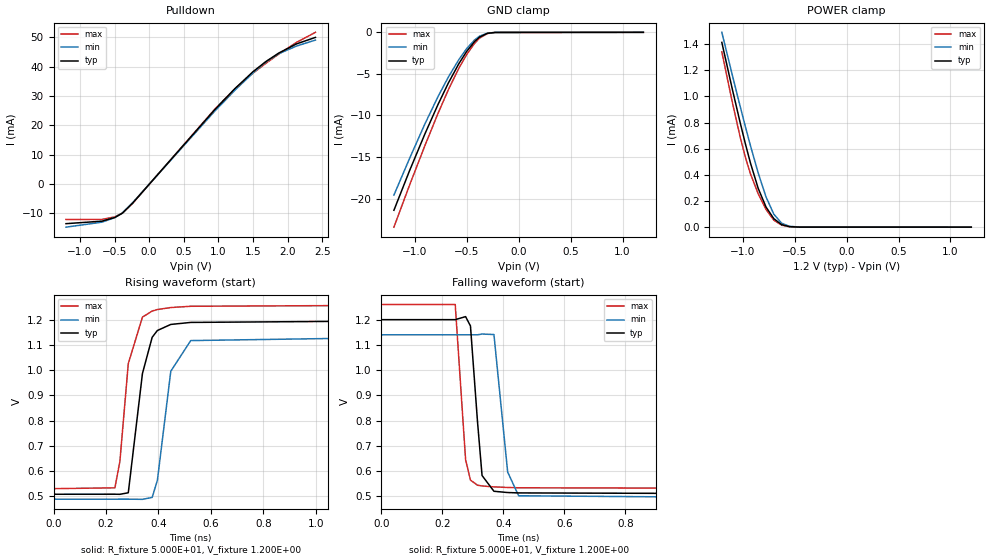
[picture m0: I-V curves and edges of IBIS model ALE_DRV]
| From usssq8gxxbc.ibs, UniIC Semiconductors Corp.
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|   Model ALE_DRV
[Model] ALE_DRV
Model_type Open_sink
Polarity   Non-Inverting
Enable   Active-High
Vmeas =  6.000E-01
Rref =  5.000E+01
Vref =  1.200E+00
C_comp   4.640E-13   4.486E-13   4.837E-13
C_comp_pulldown   3.035E-13   2.970E-13   3.357E-13
C_comp_power_clamp   1.302E-13   1.265E-13   1.391E-13
[Model Spec]
Vmeas   6.000E-01   5.700E-01   6.300E-01
Vref   1.200E+00   1.140E+00   1.260E+00
Rref   5.000E+01   5.000E+01   5.000E+01
[Temperature Range]   4.500E+01   9.500E+01   0.000E+00
[Voltage Range]   1.200E+00   1.140E+00   1.260E+00
[C Comp Corner]
C_comp_pulldown   3.035E-13   2.970E-13   3.357E-13
C_comp_power_clamp   1.391E-13   1.302E-13   1.265E-13
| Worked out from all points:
|   slope of the pulldown table from 0 to 0.18 V, typ, clamps not added: 36.4 ohm
|   GND clamp passes 1 mA (typ) near -0.41 V on its own axis
|   POWER clamp passes 1 mA (typ) near -1.08 V on its own axis
|   rising waveform, R_fixture 5.000E+01, V_fixture 1.200E+00: 20-80 % time 45.7ps typ, 48.5ps min, 43.4ps max; typ from 0.508 V to 1.2 V
|   falling waveform, R_fixture 5.000E+01, V_fixture 1.200E+00: 20-80 % time 22.2ps typ, 26.4ps min, 20.2ps max; typ from 1.2 V to 0.508 V
[Pulldown]
|Voltage   I(typ)   I(min)   I(max)
-1.2V     -13.58mA   -14.77mA   -12.15mA
-682mV    -12.73mA   -13.07mA   -12.13mA
-497mV    -11.49mA   -11.54mA   -11.27mA
-386mV    -9.998mA   -9.897mA   -9.976mA
-238mV    -6.556mA   -6.414mA   -6.639mA
946mV     25.31mA    24.82mA    25.48mA
1.242V    32.61mA    32.07mA    32.58mA
1.501V    38.36mA    37.95mA    37.85mA
1.686V    41.79mA    41.61mA    41.18mA
1.871V    44.68mA    44.45mA    44.32mA
2.13V     47.83mA    47.09mA    48.36mA
2.4V      50.02mA    49.11mA    51.75mA
[GND_clamp]
|Voltage   I(typ)   I(min)   I(max)
-1.2V     -21.41mA   -19.58mA   -23.44mA
-1.05V    -16.66mA   -15.19mA   -18.4mA
-900mV    -12.17mA   -10.97mA   -13.57mA
-775mV    -8.663mA   -7.718mA   -9.731mA
-675mV    -6.07mA    -5.357mA   -6.872mA
-575mV    -3.768mA   -3.276mA   -4.32mA
-500mV    -2.298mA   -1.958mA   -2.676mA
-425mV    -1.123mA   -929.9uA   -1.344mA
-375mV    -561.1uA   -457.6uA   -689.4uA
-300mV    -117.3uA   -101.1uA   -143uA
-225mV    -12.89uA   -13.99uA   -12.5uA
1.2V      0A         0A         0A
[POWER_clamp]
|Voltage   I(typ)   I(min)   I(max)
-1.2V     1.414mA    1.491mA    1.341mA
-1.1V     1.059mA    1.166mA    959.1uA
-1.025V   804.3uA    928.4uA    694.9uA
-975mV    642.7uA    774.1uA    539.3uA
-925mV    491.6uA    624.7uA    408.5uA
-850mV    296.4uA    414.1uA    255.5uA
-775mV    154.4uA    231.8uA    135.8uA
-700mV    65.09uA    99.41uA    53.85uA
-625mV    19.16uA    30.35uA    15.25uA
-550mV    3.935uA    6.436uA    3.094uA
-450mV    345.4nA    637.5nA    233.6nA
1.2V      0A         0A         1.66nA
[Ramp]
| variable   typ   min   max
dV/dt_r   4.152E-01/4.872E-11   3.909E-01/5.210E-11   4.379E-01/4.447E-11
dV/dt_f   4.152E-01/2.548E-11   3.909E-01/3.119E-11   4.379E-01/2.228E-11
R_load = 5.000E+01
[Rising Waveform]
R_fixture= 5.000E+01
V_fixture= 1.200E+00
V_fixture_min= 1.140E+00
V_fixture_max= 1.260E+00
|time   V(typ)   V(min)   V(max)
0s        508.1mV    488.4mV    530.2mV
234ps     508.2mV    488.5mV    533.5mV
253ps     507.8mV    488.6mV    638.2mV
285ps     513.9mV    488.6mV    1.026V
339ps     986.7mV    487.9mV    1.21V
376ps     1.13V      495.4mV    1.234V
396ps     1.157V     563.6mV    1.24V
447ps     1.181V     995.5mV    1.248V
523ps     1.189V     1.117V     1.253V
2ns       1.2V       1.14V      1.26V
[Falling Waveform]
R_fixture= 5.000E+01
V_fixture= 1.200E+00
V_fixture_min= 1.140E+00
V_fixture_max= 1.260E+00
|time   V(typ)   V(min)   V(max)
0s        1.2V       1.14V      1.26V
242ps     1.2V       1.14V      1.26V
276ps     1.212V     1.14V      645.2mV
292ps     1.175V     1.14V      564.7mV
315ps     797.2mV    1.14V      544.4mV
330ps     582.8mV    1.143V     541.4mV
369ps     520.3mV    1.141V     537.7mV
414ps     515.3mV    596.4mV    535.4mV
450ps     513.8mV    502.5mV    534.1mV
2ns       508.1mV    488.4mV    530.2mV
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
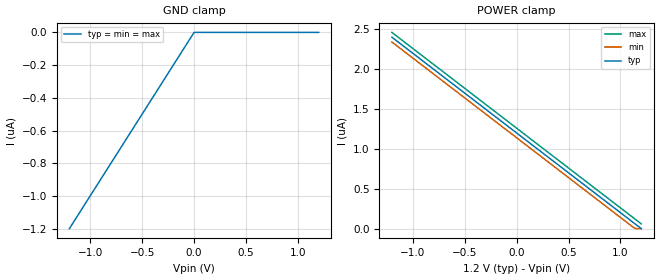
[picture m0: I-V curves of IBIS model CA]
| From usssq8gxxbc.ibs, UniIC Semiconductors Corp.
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|   Model CA
[Model] CA
Model_type Input
Polarity   Non-Inverting
Enable   Active-High
Vinl =  5.100E-01
Vinh =  6.900E-01
C_comp   -0.000E+00   -0.000E+00   -0.000E+00
[Model Spec]
Vinh   6.900E-01   6.600E-01   7.200E-01
Vinl   5.100E-01   4.800E-01   5.400E-01
[Temperature Range]   4.500E+01   9.500E+01   0.000E+00
[Voltage Range]   1.200E+00   1.140E+00   1.260E+00
[C Comp Corner]
C_comp   -0.000E+00   -0.000E+00   -0.000E+00
[GND_clamp]
|Voltage   I(typ)   I(min)   I(max)
-1.2V     -1.2uA     -1.2uA     -1.2uA
-1.075V   -1.075uA   -1.075uA   -1.075uA
0V        0A         0A         0A
1.2V      0A         0A         0A
[POWER_clamp]
|Voltage   I(typ)   I(min)   I(max)
-1.2V     2.4uA      2.34uA     2.46uA
1.125V    75nA       15nA       135nA
1.15V     50nA       0A         110nA
1.2V      0A         0A         60nA
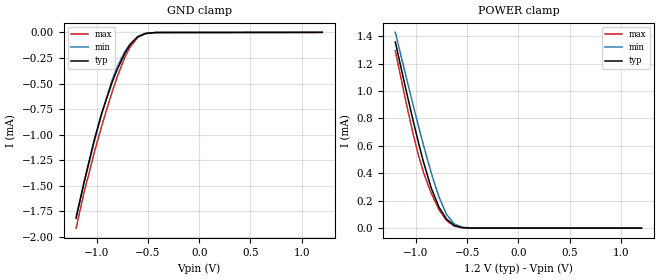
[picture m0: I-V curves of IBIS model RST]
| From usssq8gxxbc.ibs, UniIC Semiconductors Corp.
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|   Model RST
[Model] RST
Model_type Input
Polarity   Non-Inverting
Enable   Active-High
Vinl =  2.400E-01
Vinh =  9.600E-01
C_comp   3.325E-13   3.183E-13   3.499E-13
C_comp_power_clamp   1.183E-13   1.092E-13   1.358E-13
C_comp_gnd_clamp   1.941E-13   1.623E-13   2.205E-13
[Model Spec]
Vinh   9.600E-01   9.120E-01   1.008E+00
Vinl   2.400E-01   2.280E-01   2.520E-01
[Temperature Range]   4.500E+01   9.500E+01   0.000E+00
[Voltage Range]   1.200E+00   1.140E+00   1.260E+00
[C Comp Corner]
C_comp_power_clamp   1.183E-13   1.358E-13   1.092E-13
C_comp_gnd_clamp   1.941E-13   1.623E-13   2.205E-13
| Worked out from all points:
|   GND clamp passes 1 mA (typ) near -1.01 V on its own axis
|   POWER clamp passes 1 mA (typ) near -1.09 V on its own axis
[GND_clamp]
|Voltage   I(typ)   I(min)   I(max)
-1.2V     -1.816mA   -1.797mA   -1.913mA
-1.125V   -1.474mA   -1.481mA   -1.574mA
-1.025V   -1.057mA   -1.076mA   -1.18mA
-950mV    -787.4uA   -793.9uA   -912.4uA
-850mV    -490.5uA   -468.5uA   -584.5uA
-800mV    -364.5uA   -337.8uA   -436uA
-725mV    -204.3uA   -187.1uA   -243.5uA
-675mV    -121.3uA   -114.6uA   -144.9uA
-600mV    -42.01uA   -44.1uA    -50.98uA
-525mV    -10.75uA   -12.45uA   -11.9uA
-425mV    -1.264uA   -1.773uA   -1.033uA
1.2V      0A         0A         0A
[POWER_clamp]
|Voltage   I(typ)   I(min)   I(max)
-1.2V     1.357mA    1.427mA    1.293mA
-1.1V     1.021mA    1.119mA    932.1uA
-1.025V   779.4uA    893uA      681.4uA
-975mV    625.7uA    746.2uA    532.4uA
-925mV    481.4uA    603.8uA    405.5uA
-850mV    293uA      402.8uA    254.4uA
-775mV    153.6uA    227.5uA    135.3uA
-700mV    64.89uA    98.55uA    53.68uA
-625mV    19.08uA    30.18uA    15.18uA
-550mV    3.878uA    6.332uA    3.05uA
-450mV    297.8nA    543.7nA    201.6nA
1.2V      0A         0A         0A
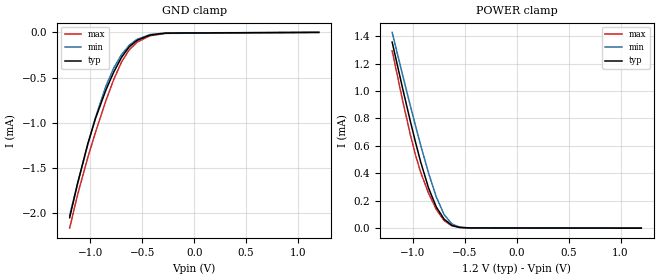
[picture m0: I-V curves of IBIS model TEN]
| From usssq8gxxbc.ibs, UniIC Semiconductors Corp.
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|   Model TEN
[Model] TEN
Model_type Input
Polarity   Non-Inverting
Enable   Active-High
Vinl =  2.400E-01
Vinh =  9.600E-01
C_comp   3.492E-13   3.289E-13   3.712E-13
C_comp_power_clamp   1.329E-13   1.234E-13   1.366E-13
C_comp_gnd_clamp   1.962E-13   1.854E-13   2.144E-13
[Model Spec]
Vinh   9.600E-01   9.120E-01   1.008E+00
Vinl   2.400E-01   2.280E-01   2.520E-01
[Temperature Range]   4.500E+01   9.500E+01   0.000E+00
[Voltage Range]   1.200E+00   1.140E+00   1.260E+00
[C Comp Corner]
C_comp_power_clamp   1.329E-13   1.234E-13   1.366E-13
C_comp_gnd_clamp   1.962E-13   1.854E-13   2.144E-13
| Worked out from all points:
|   GND clamp passes 1 mA (typ) near -0.96 V on its own axis
|   POWER clamp passes 1 mA (typ) near -1.09 V on its own axis
[GND_clamp]
|Voltage   I(typ)   I(min)   I(max)
-1.2V     -2.049mA   -2.024mA   -2.164mA
-1.125V   -1.676mA   -1.677mA   -1.8mA
-1.025V   -1.231mA   -1.238mA   -1.382mA
-950mV    -947.7uA   -935.8uA   -1.1mA
-850mV    -634.9uA   -591.8uA   -752.3uA
-775mV    -438.3uA   -393.1uA   -520uA
-700mV    -275.8uA   -245.3uA   -326.9uA
-625mV    -158.1uA   -141.4uA   -191.2uA
-550mV    -87.55uA   -75.75uA   -107.4uA
-425mV    -29.86uA   -24.07uA   -37.72uA
-275mV    -8.207uA   -6.265uA   -11uA
1.2V      0A         0A         0A
[POWER_clamp]
|Voltage   I(typ)   I(min)   I(max)
-1.2V     1.357mA    1.428mA    1.294mA
-1.1V     1.022mA    1.119mA    933uA
-1.025V   780.1uA    893.4uA    682.4uA
-975mV    626.4uA    746.6uA    533.5uA
-925mV    482.1uA    604.3uA    406.7uA
-850mV    293.8uA    403.3uA    255.7uA
-775mV    154.6uA    228.1uA    136.7uA
-700mV    65.91uA    99.19uA    55.16uA
-625mV    20.17uA    30.94uA    16.75uA
-550mV    5.011uA    7.13uA     4.663uA
-450mV    1.445uA    1.356uA    1.829uA
1.2V      0A         0A         1.865uA
